VERSION 5.7 ;
  NOWIREEXTENSIONATPIN ON ;
  DIVIDERCHAR "/" ;
  BUSBITCHARS "[]" ;
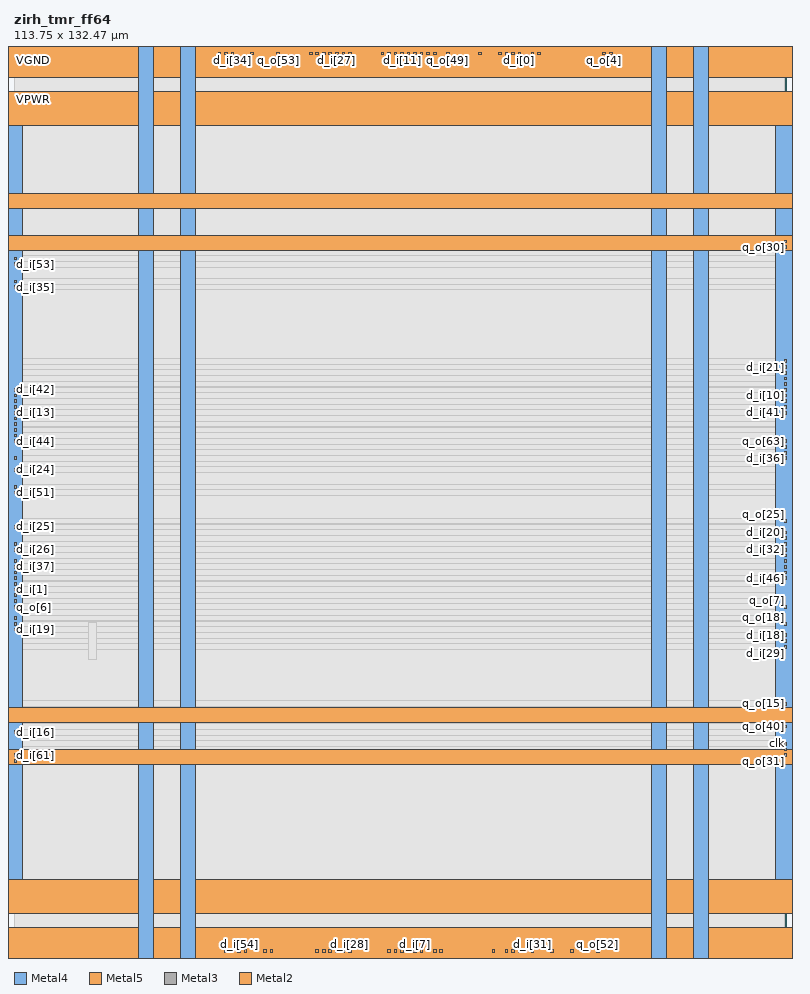
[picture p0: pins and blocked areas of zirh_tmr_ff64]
MACRO zirh_tmr_ff64
  CLASS BLOCK ;
  FOREIGN zirh_tmr_ff64 ;
  ORIGIN 0.000 0.000 ;
  SIZE 113.750 BY 132.470 ;
  PIN VGND
    DIRECTION INOUT ;
    USE GROUND ;
    PORT
      LAYER Metal4 ;
        RECT -10.740 -1.380 -5.740 133.680 ;
    END
    PORT
      LAYER Metal4 ;
        RECT 119.020 -1.380 124.020 133.680 ;
    END
    PORT
      LAYER Metal5 ;
        RECT -10.740 -1.380 124.020 3.620 ;
    END
    PORT
      LAYER Metal5 ;
        RECT -10.740 128.680 124.020 133.680 ;
    END
    PORT
      LAYER Metal4 ;
        RECT 24.460 -1.380 26.660 133.680 ;
    END
    PORT
      LAYER Metal4 ;
        RECT 100.060 -1.380 102.260 133.680 ;
    END
    PORT
      LAYER Metal5 ;
        RECT -10.740 33.820 124.020 36.020 ;
    END
    PORT
      LAYER Metal5 ;
        RECT -10.740 109.420 124.020 111.620 ;
    END
  END VGND
  PIN VPWR
    DIRECTION INOUT ;
    USE POWER ;
    PORT
      LAYER Metal4 ;
        RECT -3.740 5.620 1.260 126.680 ;
    END
    PORT
      LAYER Metal4 ;
        RECT 112.020 5.620 117.020 126.680 ;
    END
    PORT
      LAYER Metal5 ;
        RECT -3.740 5.620 117.020 10.620 ;
    END
    PORT
      LAYER Metal5 ;
        RECT -3.740 121.680 117.020 126.680 ;
    END
    PORT
      LAYER Metal4 ;
        RECT 18.260 -1.380 20.460 133.680 ;
    END
    PORT
      LAYER Metal4 ;
        RECT 93.860 -1.380 96.060 133.680 ;
    END
    PORT
      LAYER Metal5 ;
        RECT -10.740 27.620 124.020 29.820 ;
    END
    PORT
      LAYER Metal5 ;
        RECT -10.740 103.220 124.020 105.420 ;
    END
  END VPWR
  PIN clk
    DIRECTION INPUT ;
    USE SIGNAL ;
    ANTENNAGATEAREA 1.450800 ;
    PORT
      LAYER Metal3 ;
        RECT 113.350 30.460 113.750 30.860 ;
    END
  END clk
  PIN d_i[0]
    DIRECTION INPUT ;
    USE SIGNAL ;
    ANTENNAGATEAREA 0.180700 ;
    PORT
      LAYER Metal2 ;
        RECT 74.200 132.070 74.600 132.470 ;
    END
  END d_i[0]
  PIN d_i[10]
    DIRECTION INPUT ;
    USE SIGNAL ;
    ANTENNAGATEAREA 0.180700 ;
    PORT
      LAYER Metal3 ;
        RECT 113.350 81.700 113.750 82.100 ;
    END
  END d_i[10]
  PIN d_i[11]
    DIRECTION INPUT ;
    USE SIGNAL ;
    ANTENNAGATEAREA 0.180700 ;
    PORT
      LAYER Metal2 ;
        RECT 56.920 132.070 57.320 132.470 ;
    END
  END d_i[11]
  PIN d_i[12]
    DIRECTION INPUT ;
    USE SIGNAL ;
    ANTENNAGATEAREA 0.180700 ;
    PORT
      LAYER Metal2 ;
        RECT 44.440 0.000 44.840 0.400 ;
    END
  END d_i[12]
  PIN d_i[13]
    DIRECTION INPUT ;
    USE SIGNAL ;
    ANTENNAGATEAREA 0.180700 ;
    PORT
      LAYER Metal3 ;
        RECT 0.000 79.180 0.400 79.580 ;
    END
  END d_i[13]
  PIN d_i[14]
    DIRECTION INPUT ;
    USE SIGNAL ;
    ANTENNAGATEAREA 0.180700 ;
    PORT
      LAYER Metal3 ;
        RECT 0.000 52.300 0.400 52.700 ;
    END
  END d_i[14]
  PIN d_i[15]
    DIRECTION INPUT ;
    USE SIGNAL ;
    ANTENNAGATEAREA 0.180700 ;
    PORT
      LAYER Metal2 ;
        RECT 81.880 0.000 82.280 0.400 ;
    END
  END d_i[15]
  PIN d_i[16]
    DIRECTION INPUT ;
    USE SIGNAL ;
    ANTENNAGATEAREA 0.180700 ;
    PORT
      LAYER Metal3 ;
        RECT 0.000 32.140 0.400 32.540 ;
    END
  END d_i[16]
  PIN d_i[17]
    DIRECTION INPUT ;
    USE SIGNAL ;
    ANTENNAGATEAREA 0.180700 ;
    PORT
      LAYER Metal3 ;
        RECT 0.000 53.980 0.400 54.380 ;
    END
  END d_i[17]
  PIN d_i[18]
    DIRECTION INPUT ;
    USE SIGNAL ;
    ANTENNAGATEAREA 0.180700 ;
    PORT
      LAYER Metal3 ;
        RECT 113.350 46.420 113.750 46.820 ;
    END
  END d_i[18]
  PIN d_i[19]
    DIRECTION INPUT ;
    USE SIGNAL ;
    ANTENNAGATEAREA 0.180700 ;
    PORT
      LAYER Metal3 ;
        RECT 0.000 47.260 0.400 47.660 ;
    END
  END d_i[19]
  PIN d_i[1]
    DIRECTION INPUT ;
    USE SIGNAL ;
    ANTENNAGATEAREA 0.180700 ;
    PORT
      LAYER Metal3 ;
        RECT 0.000 53.140 0.400 53.540 ;
    END
  END d_i[1]
  PIN d_i[20]
    DIRECTION INPUT ;
    USE SIGNAL ;
    ANTENNAGATEAREA 0.180700 ;
    PORT
      LAYER Metal3 ;
        RECT 113.350 61.540 113.750 61.940 ;
    END
  END d_i[20]
  PIN d_i[21]
    DIRECTION INPUT ;
    USE SIGNAL ;
    ANTENNAGATEAREA 0.180700 ;
    PORT
      LAYER Metal3 ;
        RECT 113.350 85.900 113.750 86.300 ;
    END
  END d_i[21]
  PIN d_i[22]
    DIRECTION INPUT ;
    USE SIGNAL ;
    ANTENNAGATEAREA 0.180700 ;
    PORT
      LAYER Metal3 ;
        RECT 0.000 55.660 0.400 56.060 ;
    END
  END d_i[22]
  PIN d_i[23]
    DIRECTION INPUT ;
    USE SIGNAL ;
    ANTENNAGATEAREA 0.180700 ;
    PORT
      LAYER Metal3 ;
        RECT 0.000 80.860 0.400 81.260 ;
    END
  END d_i[23]
  PIN d_i[24]
    DIRECTION INPUT ;
    USE SIGNAL ;
    ANTENNAGATEAREA 0.180700 ;
    PORT
      LAYER Metal3 ;
        RECT 0.000 70.780 0.400 71.180 ;
    END
  END d_i[24]
  PIN d_i[25]
    DIRECTION INPUT ;
    USE SIGNAL ;
    ANTENNAGATEAREA 0.180700 ;
    PORT
      LAYER Metal3 ;
        RECT 0.000 62.380 0.400 62.780 ;
    END
  END d_i[25]
  PIN d_i[26]
    DIRECTION INPUT ;
    USE SIGNAL ;
    ANTENNAGATEAREA 0.180700 ;
    PORT
      LAYER Metal3 ;
        RECT 0.000 59.020 0.400 59.420 ;
    END
  END d_i[26]
  PIN d_i[27]
    DIRECTION INPUT ;
    USE SIGNAL ;
    ANTENNAGATEAREA 0.180700 ;
    PORT
      LAYER Metal2 ;
        RECT 47.320 132.070 47.720 132.470 ;
    END
  END d_i[27]
  PIN d_i[28]
    DIRECTION INPUT ;
    USE SIGNAL ;
    ANTENNAGATEAREA 0.180700 ;
    PORT
      LAYER Metal2 ;
        RECT 49.240 0.000 49.640 0.400 ;
    END
  END d_i[28]
  PIN d_i[29]
    DIRECTION INPUT ;
    USE SIGNAL ;
    ANTENNAGATEAREA 0.180700 ;
    PORT
      LAYER Metal3 ;
        RECT 113.350 44.740 113.750 45.140 ;
    END
  END d_i[29]
  PIN d_i[2]
    DIRECTION INPUT ;
    USE SIGNAL ;
    ANTENNAGATEAREA 0.180700 ;
    PORT
      LAYER Metal2 ;
        RECT 55.000 132.070 55.400 132.470 ;
    END
  END d_i[2]
  PIN d_i[30]
    DIRECTION INPUT ;
    USE SIGNAL ;
    ANTENNAGATEAREA 0.180700 ;
    PORT
      LAYER Metal2 ;
        RECT 76.120 132.070 76.520 132.470 ;
    END
  END d_i[30]
  PIN d_i[31]
    DIRECTION INPUT ;
    USE SIGNAL ;
    ANTENNAGATEAREA 0.180700 ;
    PORT
      LAYER Metal2 ;
        RECT 76.120 0.000 76.520 0.400 ;
    END
  END d_i[31]
  PIN d_i[32]
    DIRECTION INPUT ;
    USE SIGNAL ;
    ANTENNAGATEAREA 0.180700 ;
    PORT
      LAYER Metal3 ;
        RECT 113.350 59.020 113.750 59.420 ;
    END
  END d_i[32]
  PIN d_i[33]
    DIRECTION INPUT ;
    USE SIGNAL ;
    ANTENNAGATEAREA 0.180700 ;
    PORT
      LAYER Metal3 ;
        RECT 113.350 82.540 113.750 82.940 ;
    END
  END d_i[33]
  PIN d_i[34]
    DIRECTION INPUT ;
    USE SIGNAL ;
    ANTENNAGATEAREA 0.180700 ;
    PORT
      LAYER Metal2 ;
        RECT 31.960 132.070 32.360 132.470 ;
    END
  END d_i[34]
  PIN d_i[35]
    DIRECTION INPUT ;
    USE SIGNAL ;
    ANTENNAGATEAREA 0.180700 ;
    PORT
      LAYER Metal3 ;
        RECT 0.000 97.660 0.400 98.060 ;
    END
  END d_i[35]
  PIN d_i[36]
    DIRECTION INPUT ;
    USE SIGNAL ;
    ANTENNAGATEAREA 0.180700 ;
    PORT
      LAYER Metal3 ;
        RECT 113.350 72.460 113.750 72.860 ;
    END
  END d_i[36]
  PIN d_i[37]
    DIRECTION INPUT ;
    USE SIGNAL ;
    ANTENNAGATEAREA 0.180700 ;
    PORT
      LAYER Metal3 ;
        RECT 0.000 56.500 0.400 56.900 ;
    END
  END d_i[37]
  PIN d_i[38]
    DIRECTION INPUT ;
    USE SIGNAL ;
    ANTENNAGATEAREA 0.180700 ;
    PORT
      LAYER Metal2 ;
        RECT 47.320 0.000 47.720 0.400 ;
    END
  END d_i[38]
  PIN d_i[39]
    DIRECTION INPUT ;
    USE SIGNAL ;
    ANTENNAGATEAREA 0.180700 ;
    PORT
      LAYER Metal3 ;
        RECT 0.000 98.500 0.400 98.900 ;
    END
  END d_i[39]
  PIN d_i[3]
    DIRECTION INPUT ;
    USE SIGNAL ;
    ANTENNAGATEAREA 0.180700 ;
    PORT
      LAYER Metal2 ;
        RECT 61.720 132.070 62.120 132.470 ;
    END
  END d_i[3]
  PIN d_i[40]
    DIRECTION INPUT ;
    USE SIGNAL ;
    ANTENNAGATEAREA 0.180700 ;
    PORT
      LAYER Metal2 ;
        RECT 74.200 0.000 74.600 0.400 ;
    END
  END d_i[40]
  PIN d_i[41]
    DIRECTION INPUT ;
    USE SIGNAL ;
    ANTENNAGATEAREA 0.180700 ;
    PORT
      LAYER Metal3 ;
        RECT 113.350 79.180 113.750 79.580 ;
    END
  END d_i[41]
  PIN d_i[42]
    DIRECTION INPUT ;
    USE SIGNAL ;
    ANTENNAGATEAREA 0.180700 ;
    PORT
      LAYER Metal3 ;
        RECT 0.000 82.540 0.400 82.940 ;
    END
  END d_i[42]
  PIN d_i[43]
    DIRECTION INPUT ;
    USE SIGNAL ;
    ANTENNAGATEAREA 0.180700 ;
    PORT
      LAYER Metal3 ;
        RECT 0.000 48.940 0.400 49.340 ;
    END
  END d_i[43]
  PIN d_i[44]
    DIRECTION INPUT ;
    USE SIGNAL ;
    ANTENNAGATEAREA 0.180700 ;
    PORT
      LAYER Metal3 ;
        RECT 0.000 74.980 0.400 75.380 ;
    END
  END d_i[44]
  PIN d_i[45]
    DIRECTION INPUT ;
    USE SIGNAL ;
    ANTENNAGATEAREA 0.180700 ;
    PORT
      LAYER Metal2 ;
        RECT 34.840 132.070 35.240 132.470 ;
    END
  END d_i[45]
  PIN d_i[46]
    DIRECTION INPUT ;
    USE SIGNAL ;
    ANTENNAGATEAREA 0.180700 ;
    PORT
      LAYER Metal3 ;
        RECT 113.350 54.820 113.750 55.220 ;
    END
  END d_i[46]
  PIN d_i[47]
    DIRECTION INPUT ;
    USE SIGNAL ;
    ANTENNAGATEAREA 0.180700 ;
    PORT
      LAYER Metal2 ;
        RECT 79.000 0.000 79.400 0.400 ;
    END
  END d_i[47]
  PIN d_i[48]
    DIRECTION INPUT ;
    USE SIGNAL ;
    ANTENNAGATEAREA 0.180700 ;
    PORT
      LAYER Metal2 ;
        RECT 77.080 132.070 77.480 132.470 ;
    END
  END d_i[48]
  PIN d_i[49]
    DIRECTION INPUT ;
    USE SIGNAL ;
    ANTENNAGATEAREA 0.180700 ;
    PORT
      LAYER Metal2 ;
        RECT 49.240 132.070 49.640 132.470 ;
    END
  END d_i[49]
  PIN d_i[4]
    DIRECTION INPUT ;
    USE SIGNAL ;
    ANTENNAGATEAREA 0.180700 ;
    PORT
      LAYER Metal2 ;
        RECT 73.240 132.070 73.640 132.470 ;
    END
  END d_i[4]
  PIN d_i[50]
    DIRECTION INPUT ;
    USE SIGNAL ;
    ANTENNAGATEAREA 0.180700 ;
    PORT
      LAYER Metal2 ;
        RECT 57.880 132.070 58.280 132.470 ;
    END
  END d_i[50]
  PIN d_i[51]
    DIRECTION INPUT ;
    USE SIGNAL ;
    ANTENNAGATEAREA 0.180700 ;
    PORT
      LAYER Metal3 ;
        RECT 0.000 67.420 0.400 67.820 ;
    END
  END d_i[51]
  PIN d_i[52]
    DIRECTION INPUT ;
    USE SIGNAL ;
    ANTENNAGATEAREA 0.180700 ;
    PORT
      LAYER Metal2 ;
        RECT 72.280 0.000 72.680 0.400 ;
    END
  END d_i[52]
  PIN d_i[53]
    DIRECTION INPUT ;
    USE SIGNAL ;
    ANTENNAGATEAREA 0.180700 ;
    PORT
      LAYER Metal3 ;
        RECT 0.000 101.020 0.400 101.420 ;
    END
  END d_i[53]
  PIN d_i[54]
    DIRECTION INPUT ;
    USE SIGNAL ;
    ANTENNAGATEAREA 0.180700 ;
    PORT
      LAYER Metal2 ;
        RECT 32.920 0.000 33.320 0.400 ;
    END
  END d_i[54]
  PIN d_i[55]
    DIRECTION INPUT ;
    USE SIGNAL ;
    ANTENNAGATEAREA 0.180700 ;
    PORT
      LAYER Metal2 ;
        RECT 43.480 132.070 43.880 132.470 ;
    END
  END d_i[55]
  PIN d_i[56]
    DIRECTION INPUT ;
    USE SIGNAL ;
    ANTENNAGATEAREA 0.180700 ;
    PORT
      LAYER Metal3 ;
        RECT 113.350 55.660 113.750 56.060 ;
    END
  END d_i[56]
  PIN d_i[57]
    DIRECTION INPUT ;
    USE SIGNAL ;
    ANTENNAGATEAREA 0.180700 ;
    PORT
      LAYER Metal3 ;
        RECT 0.000 75.820 0.400 76.220 ;
    END
  END d_i[57]
  PIN d_i[58]
    DIRECTION INPUT ;
    USE SIGNAL ;
    ANTENNAGATEAREA 0.180700 ;
    PORT
      LAYER Metal2 ;
        RECT 31.000 0.000 31.400 0.400 ;
    END
  END d_i[58]
  PIN d_i[59]
    DIRECTION INPUT ;
    USE SIGNAL ;
    ANTENNAGATEAREA 0.180700 ;
    PORT
      LAYER Metal2 ;
        RECT 55.000 0.000 55.400 0.400 ;
    END
  END d_i[59]
  PIN d_i[5]
    DIRECTION INPUT ;
    USE SIGNAL ;
    ANTENNAGATEAREA 0.180700 ;
    PORT
      LAYER Metal2 ;
        RECT 59.800 0.000 60.200 0.400 ;
    END
  END d_i[5]
  PIN d_i[60]
    DIRECTION INPUT ;
    USE SIGNAL ;
    ANTENNAGATEAREA 0.180700 ;
    PORT
      LAYER Metal2 ;
        RECT 46.360 132.070 46.760 132.470 ;
    END
  END d_i[60]
  PIN d_i[61]
    DIRECTION INPUT ;
    USE SIGNAL ;
    ANTENNAGATEAREA 0.180700 ;
    PORT
      LAYER Metal3 ;
        RECT 0.000 28.780 0.400 29.180 ;
    END
  END d_i[61]
  PIN d_i[62]
    DIRECTION INPUT ;
    USE SIGNAL ;
    ANTENNAGATEAREA 0.180700 ;
    PORT
      LAYER Metal3 ;
        RECT 0.000 27.940 0.400 28.340 ;
    END
  END d_i[62]
  PIN d_i[63]
    DIRECTION INPUT ;
    USE SIGNAL ;
    ANTENNAGATEAREA 0.180700 ;
    PORT
      LAYER Metal3 ;
        RECT 113.350 73.300 113.750 73.700 ;
    END
  END d_i[63]
  PIN d_i[6]
    DIRECTION INPUT ;
    USE SIGNAL ;
    ANTENNAGATEAREA 0.180700 ;
    PORT
      LAYER Metal3 ;
        RECT 0.000 50.620 0.400 51.020 ;
    END
  END d_i[6]
  PIN d_i[7]
    DIRECTION INPUT ;
    USE SIGNAL ;
    ANTENNAGATEAREA 0.180700 ;
    PORT
      LAYER Metal2 ;
        RECT 58.840 0.000 59.240 0.400 ;
    END
  END d_i[7]
  PIN d_i[8]
    DIRECTION INPUT ;
    USE SIGNAL ;
    ANTENNAGATEAREA 0.180700 ;
    PORT
      LAYER Metal2 ;
        RECT 54.040 132.070 54.440 132.470 ;
    END
  END d_i[8]
  PIN d_i[9]
    DIRECTION INPUT ;
    USE SIGNAL ;
    ANTENNAGATEAREA 0.180700 ;
    PORT
      LAYER Metal3 ;
        RECT 0.000 76.660 0.400 77.060 ;
    END
  END d_i[9]
  PIN q_o[0]
    DIRECTION OUTPUT ;
    USE SIGNAL ;
    ANTENNADIFFAREA 0.708600 ;
    PORT
      LAYER Metal2 ;
        RECT 87.640 132.070 88.040 132.470 ;
    END
  END q_o[0]
  PIN q_o[10]
    DIRECTION OUTPUT ;
    USE SIGNAL ;
    ANTENNADIFFAREA 0.708600 ;
    PORT
      LAYER Metal3 ;
        RECT 113.350 85.060 113.750 85.460 ;
    END
  END q_o[10]
  PIN q_o[11]
    DIRECTION OUTPUT ;
    USE SIGNAL ;
    ANTENNADIFFAREA 0.708600 ;
    PORT
      LAYER Metal2 ;
        RECT 71.320 132.070 71.720 132.470 ;
    END
  END q_o[11]
  PIN q_o[12]
    DIRECTION OUTPUT ;
    USE SIGNAL ;
    ANTENNADIFFAREA 0.708600 ;
    PORT
      LAYER Metal2 ;
        RECT 57.880 0.000 58.280 0.400 ;
    END
  END q_o[12]
  PIN q_o[13]
    DIRECTION OUTPUT ;
    USE SIGNAL ;
    ANTENNADIFFAREA 0.708600 ;
    PORT
      LAYER Metal3 ;
        RECT 0.000 80.020 0.400 80.420 ;
    END
  END q_o[13]
  PIN q_o[14]
    DIRECTION OUTPUT ;
    USE SIGNAL ;
    ANTENNADIFFAREA 0.708600 ;
    PORT
      LAYER Metal2 ;
        RECT 56.920 0.000 57.320 0.400 ;
    END
  END q_o[14]
  PIN q_o[15]
    DIRECTION OUTPUT ;
    USE SIGNAL ;
    ANTENNADIFFAREA 0.708600 ;
    PORT
      LAYER Metal3 ;
        RECT 113.350 36.340 113.750 36.740 ;
    END
  END q_o[15]
  PIN q_o[16]
    DIRECTION OUTPUT ;
    USE SIGNAL ;
    ANTENNADIFFAREA 0.708600 ;
    PORT
      LAYER Metal2 ;
        RECT 33.880 0.000 34.280 0.400 ;
    END
  END q_o[16]
  PIN q_o[17]
    DIRECTION OUTPUT ;
    USE SIGNAL ;
    ANTENNADIFFAREA 0.708600 ;
    PORT
      LAYER Metal2 ;
        RECT 55.960 0.000 56.360 0.400 ;
    END
  END q_o[17]
  PIN q_o[18]
    DIRECTION OUTPUT ;
    USE SIGNAL ;
    ANTENNADIFFAREA 0.708600 ;
    PORT
      LAYER Metal3 ;
        RECT 113.350 48.100 113.750 48.500 ;
    END
  END q_o[18]
  PIN q_o[19]
    DIRECTION OUTPUT ;
    USE SIGNAL ;
    ANTENNADIFFAREA 0.708600 ;
    PORT
      LAYER Metal3 ;
        RECT 0.000 48.100 0.400 48.500 ;
    END
  END q_o[19]
  PIN q_o[1]
    DIRECTION OUTPUT ;
    USE SIGNAL ;
    ANTENNADIFFAREA 0.708600 ;
    PORT
      LAYER Metal3 ;
        RECT 0.000 54.820 0.400 55.220 ;
    END
  END q_o[1]
  PIN q_o[20]
    DIRECTION OUTPUT ;
    USE SIGNAL ;
    ANTENNADIFFAREA 0.708600 ;
    PORT
      LAYER Metal3 ;
        RECT 113.350 60.700 113.750 61.100 ;
    END
  END q_o[20]
  PIN q_o[21]
    DIRECTION OUTPUT ;
    USE SIGNAL ;
    ANTENNADIFFAREA 0.708600 ;
    PORT
      LAYER Metal3 ;
        RECT 113.350 86.740 113.750 87.140 ;
    END
  END q_o[21]
  PIN q_o[22]
    DIRECTION OUTPUT ;
    USE SIGNAL ;
    ANTENNADIFFAREA 0.708600 ;
    PORT
      LAYER Metal3 ;
        RECT 0.000 57.340 0.400 57.740 ;
    END
  END q_o[22]
  PIN q_o[23]
    DIRECTION OUTPUT ;
    USE SIGNAL ;
    ANTENNADIFFAREA 0.708600 ;
    PORT
      LAYER Metal3 ;
        RECT 0.000 81.700 0.400 82.100 ;
    END
  END q_o[23]
  PIN q_o[24]
    DIRECTION OUTPUT ;
    USE SIGNAL ;
    ANTENNADIFFAREA 0.708600 ;
    PORT
      LAYER Metal3 ;
        RECT 0.000 72.460 0.400 72.860 ;
    END
  END q_o[24]
  PIN q_o[25]
    DIRECTION OUTPUT ;
    USE SIGNAL ;
    ANTENNADIFFAREA 0.708600 ;
    PORT
      LAYER Metal3 ;
        RECT 113.350 63.220 113.750 63.620 ;
    END
  END q_o[25]
  PIN q_o[26]
    DIRECTION OUTPUT ;
    USE SIGNAL ;
    ANTENNADIFFAREA 0.708600 ;
    PORT
      LAYER Metal3 ;
        RECT 0.000 59.860 0.400 60.260 ;
    END
  END q_o[26]
  PIN q_o[27]
    DIRECTION OUTPUT ;
    USE SIGNAL ;
    ANTENNADIFFAREA 0.708600 ;
    PORT
      LAYER Metal2 ;
        RECT 60.760 132.070 61.160 132.470 ;
    END
  END q_o[27]
  PIN q_o[28]
    DIRECTION OUTPUT ;
    USE SIGNAL ;
    ANTENNADIFFAREA 0.708600 ;
    PORT
      LAYER Metal2 ;
        RECT 62.680 0.000 63.080 0.400 ;
    END
  END q_o[28]
  PIN q_o[29]
    DIRECTION OUTPUT ;
    USE SIGNAL ;
    ANTENNADIFFAREA 0.708600 ;
    PORT
      LAYER Metal3 ;
        RECT 113.350 45.580 113.750 45.980 ;
    END
  END q_o[29]
  PIN q_o[2]
    DIRECTION OUTPUT ;
    USE SIGNAL ;
    ANTENNADIFFAREA 0.708600 ;
    PORT
      LAYER Metal3 ;
        RECT 113.350 83.380 113.750 83.780 ;
    END
  END q_o[2]
  PIN q_o[30]
    DIRECTION OUTPUT ;
    USE SIGNAL ;
    ANTENNADIFFAREA 0.708600 ;
    PORT
      LAYER Metal3 ;
        RECT 113.350 103.540 113.750 103.940 ;
    END
  END q_o[30]
  PIN q_o[31]
    DIRECTION OUTPUT ;
    USE SIGNAL ;
    ANTENNADIFFAREA 0.708600 ;
    PORT
      LAYER Metal3 ;
        RECT 113.350 28.780 113.750 29.180 ;
    END
  END q_o[31]
  PIN q_o[32]
    DIRECTION OUTPUT ;
    USE SIGNAL ;
    ANTENNADIFFAREA 0.708600 ;
    PORT
      LAYER Metal3 ;
        RECT 113.350 59.860 113.750 60.260 ;
    END
  END q_o[32]
  PIN q_o[33]
    DIRECTION OUTPUT ;
    USE SIGNAL ;
    ANTENNADIFFAREA 0.708600 ;
    PORT
      LAYER Metal3 ;
        RECT 113.350 84.220 113.750 84.620 ;
    END
  END q_o[33]
  PIN q_o[34]
    DIRECTION OUTPUT ;
    USE SIGNAL ;
    ANTENNADIFFAREA 0.708600 ;
    PORT
      LAYER Metal2 ;
        RECT 45.400 132.070 45.800 132.470 ;
    END
  END q_o[34]
  PIN q_o[35]
    DIRECTION OUTPUT ;
    USE SIGNAL ;
    ANTENNADIFFAREA 0.708600 ;
    PORT
      LAYER Metal2 ;
        RECT 31.000 132.070 31.400 132.470 ;
    END
  END q_o[35]
  PIN q_o[36]
    DIRECTION OUTPUT ;
    USE SIGNAL ;
    ANTENNADIFFAREA 0.708600 ;
    PORT
      LAYER Metal3 ;
        RECT 113.350 74.140 113.750 74.540 ;
    END
  END q_o[36]
  PIN q_o[37]
    DIRECTION OUTPUT ;
    USE SIGNAL ;
    ANTENNADIFFAREA 0.708600 ;
    PORT
      LAYER Metal3 ;
        RECT 113.350 58.180 113.750 58.580 ;
    END
  END q_o[37]
  PIN q_o[38]
    DIRECTION OUTPUT ;
    USE SIGNAL ;
    ANTENNADIFFAREA 0.708600 ;
    PORT
      LAYER Metal2 ;
        RECT 61.720 0.000 62.120 0.400 ;
    END
  END q_o[38]
  PIN q_o[39]
    DIRECTION OUTPUT ;
    USE SIGNAL ;
    ANTENNADIFFAREA 0.708600 ;
    PORT
      LAYER Metal2 ;
        RECT 30.040 132.070 30.440 132.470 ;
    END
  END q_o[39]
  PIN q_o[3]
    DIRECTION OUTPUT ;
    USE SIGNAL ;
    ANTENNADIFFAREA 0.708600 ;
    PORT
      LAYER Metal3 ;
        RECT 113.350 80.020 113.750 80.420 ;
    END
  END q_o[3]
  PIN q_o[40]
    DIRECTION OUTPUT ;
    USE SIGNAL ;
    ANTENNADIFFAREA 0.708600 ;
    PORT
      LAYER Metal3 ;
        RECT 113.350 32.980 113.750 33.380 ;
    END
  END q_o[40]
  PIN q_o[41]
    DIRECTION OUTPUT ;
    USE SIGNAL ;
    ANTENNADIFFAREA 0.708600 ;
    PORT
      LAYER Metal3 ;
        RECT 113.350 80.860 113.750 81.260 ;
    END
  END q_o[41]
  PIN q_o[42]
    DIRECTION OUTPUT ;
    USE SIGNAL ;
    ANTENNADIFFAREA 0.708600 ;
    PORT
      LAYER Metal2 ;
        RECT 44.440 132.070 44.840 132.470 ;
    END
  END q_o[42]
  PIN q_o[43]
    DIRECTION OUTPUT ;
    USE SIGNAL ;
    ANTENNADIFFAREA 0.708600 ;
    PORT
      LAYER Metal2 ;
        RECT 48.280 0.000 48.680 0.400 ;
    END
  END q_o[43]
  PIN q_o[44]
    DIRECTION OUTPUT ;
    USE SIGNAL ;
    ANTENNADIFFAREA 0.708600 ;
    PORT
      LAYER Metal2 ;
        RECT 55.960 132.070 56.360 132.470 ;
    END
  END q_o[44]
  PIN q_o[45]
    DIRECTION OUTPUT ;
    USE SIGNAL ;
    ANTENNADIFFAREA 0.708600 ;
    PORT
      LAYER Metal2 ;
        RECT 48.280 132.070 48.680 132.470 ;
    END
  END q_o[45]
  PIN q_o[46]
    DIRECTION OUTPUT ;
    USE SIGNAL ;
    ANTENNADIFFAREA 0.708600 ;
    PORT
      LAYER Metal3 ;
        RECT 113.350 57.340 113.750 57.740 ;
    END
  END q_o[46]
  PIN q_o[47]
    DIRECTION OUTPUT ;
    USE SIGNAL ;
    ANTENNADIFFAREA 0.708600 ;
    PORT
      LAYER Metal3 ;
        RECT 113.350 29.620 113.750 30.020 ;
    END
  END q_o[47]
  PIN q_o[48]
    DIRECTION OUTPUT ;
    USE SIGNAL ;
    ANTENNADIFFAREA 0.708600 ;
    PORT
      LAYER Metal3 ;
        RECT 113.350 104.380 113.750 104.780 ;
    END
  END q_o[48]
  PIN q_o[49]
    DIRECTION OUTPUT ;
    USE SIGNAL ;
    ANTENNADIFFAREA 0.708600 ;
    PORT
      LAYER Metal2 ;
        RECT 63.640 132.070 64.040 132.470 ;
    END
  END q_o[49]
  PIN q_o[4]
    DIRECTION OUTPUT ;
    USE SIGNAL ;
    ANTENNADIFFAREA 0.708600 ;
    PORT
      LAYER Metal2 ;
        RECT 86.680 132.070 87.080 132.470 ;
    END
  END q_o[4]
  PIN q_o[50]
    DIRECTION OUTPUT ;
    USE SIGNAL ;
    ANTENNADIFFAREA 0.708600 ;
    PORT
      LAYER Metal2 ;
        RECT 72.280 132.070 72.680 132.470 ;
    END
  END q_o[50]
  PIN q_o[51]
    DIRECTION OUTPUT ;
    USE SIGNAL ;
    ANTENNADIFFAREA 0.708600 ;
    PORT
      LAYER Metal3 ;
        RECT 0.000 68.260 0.400 68.660 ;
    END
  END q_o[51]
  PIN q_o[52]
    DIRECTION OUTPUT ;
    USE SIGNAL ;
    ANTENNADIFFAREA 0.708600 ;
    PORT
      LAYER Metal2 ;
        RECT 85.720 0.000 86.120 0.400 ;
    END
  END q_o[52]
  PIN q_o[53]
    DIRECTION OUTPUT ;
    USE SIGNAL ;
    ANTENNADIFFAREA 0.708600 ;
    PORT
      LAYER Metal2 ;
        RECT 38.680 132.070 39.080 132.470 ;
    END
  END q_o[53]
  PIN q_o[54]
    DIRECTION OUTPUT ;
    USE SIGNAL ;
    ANTENNADIFFAREA 0.708600 ;
    PORT
      LAYER Metal2 ;
        RECT 46.360 0.000 46.760 0.400 ;
    END
  END q_o[54]
  PIN q_o[55]
    DIRECTION OUTPUT ;
    USE SIGNAL ;
    ANTENNADIFFAREA 0.708600 ;
    PORT
      LAYER Metal2 ;
        RECT 58.840 132.070 59.240 132.470 ;
    END
  END q_o[55]
  PIN q_o[56]
    DIRECTION OUTPUT ;
    USE SIGNAL ;
    ANTENNADIFFAREA 0.708600 ;
    PORT
      LAYER Metal3 ;
        RECT 113.350 56.500 113.750 56.900 ;
    END
  END q_o[56]
  PIN q_o[57]
    DIRECTION OUTPUT ;
    USE SIGNAL ;
    ANTENNADIFFAREA 0.708600 ;
    PORT
      LAYER Metal3 ;
        RECT 0.000 77.500 0.400 77.900 ;
    END
  END q_o[57]
  PIN q_o[58]
    DIRECTION OUTPUT ;
    USE SIGNAL ;
    ANTENNADIFFAREA 0.708600 ;
    PORT
      LAYER Metal2 ;
        RECT 45.400 0.000 45.800 0.400 ;
    END
  END q_o[58]
  PIN q_o[59]
    DIRECTION OUTPUT ;
    USE SIGNAL ;
    ANTENNADIFFAREA 0.708600 ;
    PORT
      LAYER Metal2 ;
        RECT 70.360 0.000 70.760 0.400 ;
    END
  END q_o[59]
  PIN q_o[5]
    DIRECTION OUTPUT ;
    USE SIGNAL ;
    ANTENNADIFFAREA 0.708600 ;
    PORT
      LAYER Metal2 ;
        RECT 73.240 0.000 73.640 0.400 ;
    END
  END q_o[5]
  PIN q_o[60]
    DIRECTION OUTPUT ;
    USE SIGNAL ;
    ANTENNADIFFAREA 0.708600 ;
    PORT
      LAYER Metal2 ;
        RECT 59.800 132.070 60.200 132.470 ;
    END
  END q_o[60]
  PIN q_o[61]
    DIRECTION OUTPUT ;
    USE SIGNAL ;
    ANTENNADIFFAREA 0.708600 ;
    PORT
      LAYER Metal2 ;
        RECT 37.720 0.000 38.120 0.400 ;
    END
  END q_o[61]
  PIN q_o[62]
    DIRECTION OUTPUT ;
    USE SIGNAL ;
    ANTENNADIFFAREA 0.708600 ;
    PORT
      LAYER Metal2 ;
        RECT 36.760 0.000 37.160 0.400 ;
    END
  END q_o[62]
  PIN q_o[63]
    DIRECTION OUTPUT ;
    USE SIGNAL ;
    ANTENNADIFFAREA 0.708600 ;
    PORT
      LAYER Metal3 ;
        RECT 113.350 74.980 113.750 75.380 ;
    END
  END q_o[63]
  PIN q_o[6]
    DIRECTION OUTPUT ;
    USE SIGNAL ;
    ANTENNADIFFAREA 0.708600 ;
    PORT
      LAYER Metal3 ;
        RECT 0.000 51.460 0.400 51.860 ;
    END
  END q_o[6]
  PIN q_o[7]
    DIRECTION OUTPUT ;
    USE SIGNAL ;
    ANTENNADIFFAREA 0.708600 ;
    PORT
      LAYER Metal3 ;
        RECT 113.350 50.620 113.750 51.020 ;
    END
  END q_o[7]
  PIN q_o[8]
    DIRECTION OUTPUT ;
    USE SIGNAL ;
    ANTENNADIFFAREA 0.708600 ;
    PORT
      LAYER Metal2 ;
        RECT 68.440 132.070 68.840 132.470 ;
    END
  END q_o[8]
  PIN q_o[9]
    DIRECTION OUTPUT ;
    USE SIGNAL ;
    ANTENNADIFFAREA 0.708600 ;
    PORT
      LAYER Metal3 ;
        RECT 0.000 78.340 0.400 78.740 ;
    END
  END q_o[9]
  PIN rst_n
    DIRECTION INPUT ;
    USE SIGNAL ;
    ANTENNAGATEAREA 0.180700 ;
    PORT
      LAYER Metal3 ;
        RECT 0.000 101.860 0.400 102.260 ;
    END
  END rst_n
  OBS
      LAYER GatPoly ;
        RECT 5.760 14.970 107.520 117.330 ;
      LAYER Metal1 ;
        RECT 5.760 14.900 107.520 117.400 ;
      LAYER Metal2 ;
        RECT 0.375 131.860 29.830 132.070 ;
        RECT 30.650 131.860 30.790 132.070 ;
        RECT 31.610 131.860 31.750 132.070 ;
        RECT 32.570 131.860 34.630 132.070 ;
        RECT 35.450 131.860 38.470 132.070 ;
        RECT 39.290 131.860 43.270 132.070 ;
        RECT 44.090 131.860 44.230 132.070 ;
        RECT 45.050 131.860 45.190 132.070 ;
        RECT 46.010 131.860 46.150 132.070 ;
        RECT 46.970 131.860 47.110 132.070 ;
        RECT 47.930 131.860 48.070 132.070 ;
        RECT 48.890 131.860 49.030 132.070 ;
        RECT 49.850 131.860 53.830 132.070 ;
        RECT 54.650 131.860 54.790 132.070 ;
        RECT 55.610 131.860 55.750 132.070 ;
        RECT 56.570 131.860 56.710 132.070 ;
        RECT 57.530 131.860 57.670 132.070 ;
        RECT 58.490 131.860 58.630 132.070 ;
        RECT 59.450 131.860 59.590 132.070 ;
        RECT 60.410 131.860 60.550 132.070 ;
        RECT 61.370 131.860 61.510 132.070 ;
        RECT 62.330 131.860 63.430 132.070 ;
        RECT 64.250 131.860 68.230 132.070 ;
        RECT 69.050 131.860 71.110 132.070 ;
        RECT 71.930 131.860 72.070 132.070 ;
        RECT 72.890 131.860 73.030 132.070 ;
        RECT 73.850 131.860 73.990 132.070 ;
        RECT 74.810 131.860 75.910 132.070 ;
        RECT 76.730 131.860 76.870 132.070 ;
        RECT 77.690 131.860 86.470 132.070 ;
        RECT 87.290 131.860 87.430 132.070 ;
        RECT 88.250 131.860 113.385 132.070 ;
        RECT 0.375 0.610 113.385 131.860 ;
        RECT 0.375 0.100 30.790 0.610 ;
        RECT 31.610 0.100 32.710 0.610 ;
        RECT 33.530 0.100 33.670 0.610 ;
        RECT 34.490 0.100 36.550 0.610 ;
        RECT 37.370 0.100 37.510 0.610 ;
        RECT 38.330 0.100 44.230 0.610 ;
        RECT 45.050 0.100 45.190 0.610 ;
        RECT 46.010 0.100 46.150 0.610 ;
        RECT 46.970 0.100 47.110 0.610 ;
        RECT 47.930 0.100 48.070 0.610 ;
        RECT 48.890 0.100 49.030 0.610 ;
        RECT 49.850 0.100 54.790 0.610 ;
        RECT 55.610 0.100 55.750 0.610 ;
        RECT 56.570 0.100 56.710 0.610 ;
        RECT 57.530 0.100 57.670 0.610 ;
        RECT 58.490 0.100 58.630 0.610 ;
        RECT 59.450 0.100 59.590 0.610 ;
        RECT 60.410 0.100 61.510 0.610 ;
        RECT 62.330 0.100 62.470 0.610 ;
        RECT 63.290 0.100 70.150 0.610 ;
        RECT 70.970 0.100 72.070 0.610 ;
        RECT 72.890 0.100 73.030 0.610 ;
        RECT 73.850 0.100 73.990 0.610 ;
        RECT 74.810 0.100 75.910 0.610 ;
        RECT 76.730 0.100 78.790 0.610 ;
        RECT 79.610 0.100 81.670 0.610 ;
        RECT 82.490 0.100 85.510 0.610 ;
        RECT 86.330 0.100 113.385 0.610 ;
      LAYER Metal3 ;
        RECT 0.100 104.990 113.425 131.560 ;
        RECT 0.100 104.170 113.140 104.990 ;
        RECT 0.100 104.150 113.425 104.170 ;
        RECT 0.100 103.330 113.140 104.150 ;
        RECT 0.100 102.470 113.425 103.330 ;
        RECT 0.610 101.650 113.425 102.470 ;
        RECT 0.100 101.630 113.425 101.650 ;
        RECT 0.610 100.810 113.425 101.630 ;
        RECT 0.100 99.110 113.425 100.810 ;
        RECT 0.610 98.290 113.425 99.110 ;
        RECT 0.100 98.270 113.425 98.290 ;
        RECT 0.610 97.450 113.425 98.270 ;
        RECT 0.100 87.350 113.425 97.450 ;
        RECT 0.100 86.530 113.140 87.350 ;
        RECT 0.100 86.510 113.425 86.530 ;
        RECT 0.100 85.690 113.140 86.510 ;
        RECT 0.100 85.670 113.425 85.690 ;
        RECT 0.100 84.850 113.140 85.670 ;
        RECT 0.100 84.830 113.425 84.850 ;
        RECT 0.100 84.010 113.140 84.830 ;
        RECT 0.100 83.990 113.425 84.010 ;
        RECT 0.100 83.170 113.140 83.990 ;
        RECT 0.100 83.150 113.425 83.170 ;
        RECT 0.610 82.330 113.140 83.150 ;
        RECT 0.100 82.310 113.425 82.330 ;
        RECT 0.610 81.490 113.140 82.310 ;
        RECT 0.100 81.470 113.425 81.490 ;
        RECT 0.610 80.650 113.140 81.470 ;
        RECT 0.100 80.630 113.425 80.650 ;
        RECT 0.610 79.810 113.140 80.630 ;
        RECT 0.100 79.790 113.425 79.810 ;
        RECT 0.610 78.970 113.140 79.790 ;
        RECT 0.100 78.950 113.425 78.970 ;
        RECT 0.610 78.130 113.425 78.950 ;
        RECT 0.100 78.110 113.425 78.130 ;
        RECT 0.610 77.290 113.425 78.110 ;
        RECT 0.100 77.270 113.425 77.290 ;
        RECT 0.610 76.450 113.425 77.270 ;
        RECT 0.100 76.430 113.425 76.450 ;
        RECT 0.610 75.610 113.425 76.430 ;
        RECT 0.100 75.590 113.425 75.610 ;
        RECT 0.610 74.770 113.140 75.590 ;
        RECT 0.100 74.750 113.425 74.770 ;
        RECT 0.100 73.930 113.140 74.750 ;
        RECT 0.100 73.910 113.425 73.930 ;
        RECT 0.100 73.090 113.140 73.910 ;
        RECT 0.100 73.070 113.425 73.090 ;
        RECT 0.610 72.250 113.140 73.070 ;
        RECT 0.100 71.390 113.425 72.250 ;
        RECT 0.610 70.570 113.425 71.390 ;
        RECT 0.100 68.870 113.425 70.570 ;
        RECT 0.610 68.050 113.425 68.870 ;
        RECT 0.100 68.030 113.425 68.050 ;
        RECT 0.610 67.210 113.425 68.030 ;
        RECT 0.100 63.830 113.425 67.210 ;
        RECT 0.100 63.010 113.140 63.830 ;
        RECT 0.100 62.990 113.425 63.010 ;
        RECT 0.610 62.170 113.425 62.990 ;
        RECT 0.100 62.150 113.425 62.170 ;
        RECT 0.100 61.330 113.140 62.150 ;
        RECT 0.100 61.310 113.425 61.330 ;
        RECT 0.100 60.490 113.140 61.310 ;
        RECT 0.100 60.470 113.425 60.490 ;
        RECT 0.610 59.650 113.140 60.470 ;
        RECT 0.100 59.630 113.425 59.650 ;
        RECT 0.610 58.810 113.140 59.630 ;
        RECT 0.100 58.790 113.425 58.810 ;
        RECT 0.100 57.970 113.140 58.790 ;
        RECT 0.100 57.950 113.425 57.970 ;
        RECT 0.610 57.130 113.140 57.950 ;
        RECT 0.100 57.110 113.425 57.130 ;
        RECT 0.610 56.290 113.140 57.110 ;
        RECT 0.100 56.270 113.425 56.290 ;
        RECT 0.610 55.450 113.140 56.270 ;
        RECT 0.100 55.430 113.425 55.450 ;
        RECT 0.610 54.610 113.140 55.430 ;
        RECT 0.100 54.590 113.425 54.610 ;
        RECT 0.610 53.770 113.425 54.590 ;
        RECT 0.100 53.750 113.425 53.770 ;
        RECT 0.610 52.930 113.425 53.750 ;
        RECT 0.100 52.910 113.425 52.930 ;
        RECT 0.610 52.090 113.425 52.910 ;
        RECT 0.100 52.070 113.425 52.090 ;
        RECT 0.610 51.250 113.425 52.070 ;
        RECT 0.100 51.230 113.425 51.250 ;
        RECT 0.610 50.410 113.140 51.230 ;
        RECT 0.100 49.550 113.425 50.410 ;
        RECT 0.610 48.730 113.425 49.550 ;
        RECT 0.100 48.710 113.425 48.730 ;
        RECT 0.610 47.890 113.140 48.710 ;
        RECT 0.100 47.870 113.425 47.890 ;
        RECT 0.610 47.050 113.425 47.870 ;
        RECT 0.100 47.030 113.425 47.050 ;
        RECT 0.100 46.210 113.140 47.030 ;
        RECT 0.100 46.190 113.425 46.210 ;
        RECT 0.100 45.370 113.140 46.190 ;
        RECT 0.100 45.350 113.425 45.370 ;
        RECT 0.100 44.530 113.140 45.350 ;
        RECT 0.100 36.950 113.425 44.530 ;
        RECT 0.100 36.130 113.140 36.950 ;
        RECT 0.100 33.590 113.425 36.130 ;
        RECT 0.100 32.770 113.140 33.590 ;
        RECT 0.100 32.750 113.425 32.770 ;
        RECT 0.610 31.930 113.425 32.750 ;
        RECT 0.100 31.070 113.425 31.930 ;
        RECT 0.100 30.250 113.140 31.070 ;
        RECT 0.100 30.230 113.425 30.250 ;
        RECT 0.100 29.410 113.140 30.230 ;
        RECT 0.100 29.390 113.425 29.410 ;
        RECT 0.610 28.570 113.140 29.390 ;
        RECT 0.100 28.550 113.425 28.570 ;
        RECT 0.610 27.730 113.425 28.550 ;
        RECT 0.100 0.320 113.425 27.730 ;
      LAYER Metal4 ;
        RECT 10.940 43.115 12.100 48.445 ;
  END
END zirh_tmr_ff64
END LIBRARY

